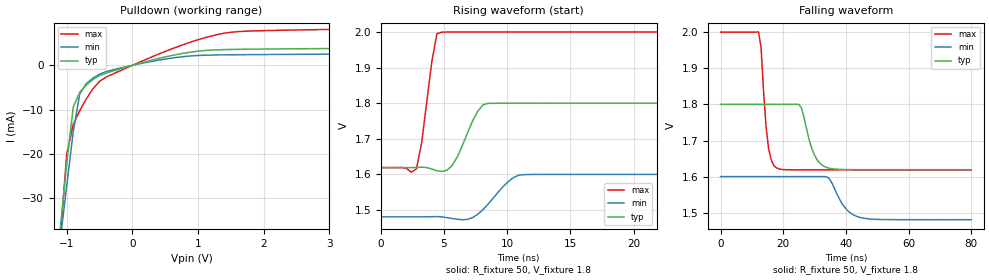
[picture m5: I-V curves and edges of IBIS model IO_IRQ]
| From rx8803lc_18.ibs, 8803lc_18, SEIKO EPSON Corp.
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[Model]   IO_IRQ
Model_type Open_drain
Enable Active-Low
Polarity Non-Inverting
C_comp   5p   4p   6p
[Temperature Range] 25   85   -40
[Voltage Range]   1.8   1.6   2.0
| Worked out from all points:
|   slope of the pulldown table from 0 to 0.27 V, typ, clamps not added: 249 ohm
|   falling waveform, R_fixture 50, V_fixture 1.8: 20-80 % time 3.62ns typ, 4.87ns min, 1.95ns max; typ from 1.8 V to 1.62 V
|   rising waveform, R_fixture 50, V_fixture 1.8: 20-80 % time 1.34ns typ, 1.8ns min, 820ps max; typ from 1.62 V to 1.8 V
[Pulldown]
-1.8V     -144.7mA   -129.8mA   -181.4mA
-1.1V     -37.27mA   -39.81mA   -39.83mA
-1V       -22.35mA   -27.36mA   -20.16mA
-900mV    -9.441mA   -15.03mA   -13.34mA
-800mV    -6.071mA   -6.414mA   -10.23mA
-700mV    -4.442mA   -4.128mA   -7.55mA
-500mV    -2.309mA   -1.999mA   -3.638mA
-200mV    -854.3uA   -663.3uA   -1.319mA
500mV     1.905mA    1.42mA     3.134mA
1.3V      3.513mA    2.352mA    6.975mA
1.8V      3.65mA     2.424mA    7.755mA
3.6V      3.86mA     2.572mA    8.241mA
[Falling Waveform]
R_fixture=50
V_fixture=1.8
V_fixture_min=1.6
V_fixture_max=2.0
0s        1.8V       1.6V       2V
12.12ns   1.8V       1.6V       2V
12.93ns   1.8V       1.6V       1.958V
15.35ns   1.8V       1.6V       1.677V
17.78ns   1.8V       1.6V       1.625V
25.05ns   1.8V       1.6V       1.619V
29.9ns    1.661V     1.6V       1.619V
33.94ns   1.625V     1.599V     1.619V
44.44ns   1.619V     1.487V     1.619V
80ns      1.619V     1.481V     1.619V
[Rising Waveform]
R_fixture=50
V_fixture=1.8
V_fixture_min=1.6
V_fixture_max=2.0
0s        1.619V     1.481V     1.619V
2.828ns   1.619V     1.481V     1.616V
3.232ns   1.62V      1.481V     1.688V
4.444ns   1.61V      1.482V     1.995V
4.848ns   1.608V     1.481V     1.999V
5.657ns   1.625V     1.476V     2V
6.869ns   1.717V     1.474V     2V
8.485ns   1.8V       1.516V     2V
11.31ns   1.8V       1.599V     2V
40ns      1.8V       1.6V       2V
[Ramp]
R_load=50
dV/dt_r   1.085E-1/1.306E-9   7.154E-2/1.785E-9   2.287E-1/8.009E-10
dV/dt_f   1.085E-1/3.585E-9   7.151E-2/4.834E-9   2.287E-1/1.899E-9
|[End   IO_IRQ
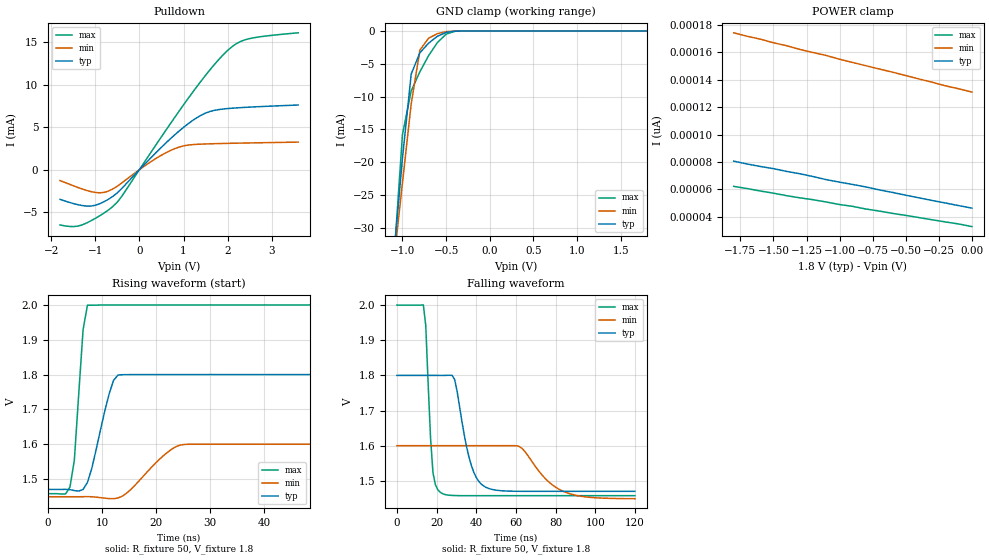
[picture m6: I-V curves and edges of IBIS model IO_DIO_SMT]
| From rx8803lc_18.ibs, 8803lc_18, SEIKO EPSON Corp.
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[Model]   IO_DIO_SMT
Model_type I/O_open_drain
Enable Active-High
Polarity Non-Inverting
Vinh=1.44
Vinl=0.36
C_comp   5p   4p   6p
[Temperature Range] 25   85   -40
[Voltage Range]   1.8   1.6   2.0
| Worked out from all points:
|   slope of the pulldown table from 0 to 0.27 V, typ, clamps not added: 186 ohm
|   GND clamp passes 1 mA (typ) near -0.62 V on its own axis
|   falling waveform, R_fixture 50, V_fixture 1.8: 20-80 % time 7.07ns typ, 14.5ns min, 2.74ns max; typ from 1.8 V to 1.47 V
|   rising waveform, R_fixture 50, V_fixture 1.8: 20-80 % time 2.96ns typ, 5.68ns min, 1.4ns max; typ from 1.47 V to 1.8 V
[Pulldown]
-1.8V     -3.505mA   -1.29mA    -6.521mA
-1.4V     -4.126mA   -2.094mA   -6.661mA
-1.1V     -4.293mA   -2.588mA   -6.028mA
-800mV    -3.771mA   -2.681mA   -5.109mA
-500mV    -2.729mA   -1.945mA   -3.818mA
500mV     2.646mA    1.707mA    3.885mA
800mV     4.101mA    2.476mA    6.158mA
1.1V      5.394mA    2.897mA    8.361mA
1.6V      6.861mA    3.048mA    11.77mA
2.1V      7.247mA    3.112mA    14.5mA
2.5V      7.375mA    3.152mA    15.46mA
3.6V      7.623mA    3.248mA    16.14mA
[GND Clamp]
-1.8V     -143.5mA   -123.6mA   -177.6mA
-1.1V     -34.38mA   -35.36mA   -35.33mA
-1V       -19.42mA   -23.16mA   -15.8mA
-900mV    -6.562mA   -11.13mA   -9.129mA
-800mV    -3.309mA   -2.897mA   -6.201mA
-700mV    -1.841mA   -1.087mA   -3.742mA
-600mV    -807.8uA   -397.8uA   -1.764mA
-500mV    -207.4uA   -91.02uA   -476.4uA
-400mV    -22.76uA   -11uA      -42.64uA
1.8V      46.04pA    135.6pA    29.33pA
[POWER Clamp]
-1.8V     80.49pA    174.4pA    62.07pA
-1.5V     75.03pA    167.1pA    57.07pA
-1.4V     72.99pA    165pA      55.25pA
-1.3V     71.28pA    162.2pA    53.66pA
-1.1V     66.96pA    157.8pA    50.59pA
-1V       65.14pA    155.1pA    48.77pA
-900mV    63.44pA    152.7pA    47.41pA
-800mV    61.62pA    150.3pA    45.47pA
-600mV    57.64pA    145.6pA    42.29pA
-200mV    49.91pA    135.6pA    36.04pA
-100mV    47.98pA    133.5pA    34.56pA
0V        46.16pA    131.1pA    32.63pA
[Falling Waveform]
R_fixture=50
V_fixture=1.8
V_fixture_min=1.6
V_fixture_max=2.0
0s        1.8V       1.6V       2V
13.33ns   1.8V       1.6V       2.001V
14.55ns   1.8V       1.6V       1.942V
18.18ns   1.8V       1.6V       1.523V
21.82ns   1.8V       1.6V       1.467V
29.09ns   1.788V     1.6V       1.458V
36.36ns   1.567V     1.6V       1.458V
43.64ns   1.486V     1.6V       1.458V
86.06ns   1.47V      1.465V     1.458V
120ns     1.47V      1.449V     1.458V
[Rising Waveform]
R_fixture=50
V_fixture=1.8
V_fixture_min=1.6
V_fixture_max=2.0
0s        1.47V      1.449V     1.458V
3.232ns   1.47V      1.449V     1.457V
4.04ns    1.469V     1.449V     1.477V
4.848ns   1.467V     1.449V     1.554V
6.465ns   1.47V      1.449V     1.929V
7.273ns   1.49V      1.449V     1.999V
11.31ns   1.746V     1.444V     2V
12.93ns   1.799V     1.445V     2V
25.05ns   1.8V       1.599V     2V
80ns      1.8V       1.6V       2V
[Ramp]
R_load=50
dV/dt_r   1.980E-1/2.942E-9   9.065E-2/5.663E-9   3.254E-1/1.375E-9
dV/dt_f   1.980E-1/7.022E-9   7.088E-2/9.527E-9   3.254E-1/2.588E-9
|[End   IO_DIO_SMT
